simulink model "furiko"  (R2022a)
settings: Solver=VariableStepAuto  StartTime=0.0  StopTime=10.0  RelTol=1e-3
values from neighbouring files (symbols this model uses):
  k = 9e9    (= 9000000000)    [electDipole.m]    (also in solvGasSei.m = 1; solvJacobi.m = 1; solvSOR.m = 1; solvSORerr.m = 1)
  m = 4*m    (= 4)    [rom_int.m]    (also in FreeOscil_Displace_Test01.m = 1; vspring.m = 1)
undefined symbols (not defined in the file or in its folder): l

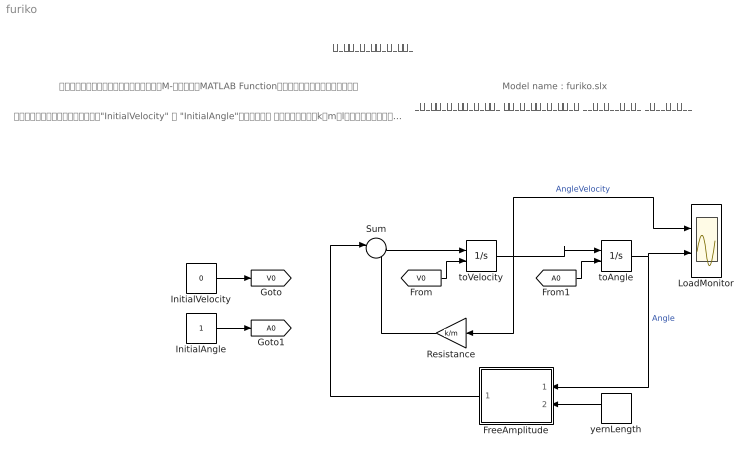
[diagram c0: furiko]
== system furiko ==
  note: コンフィギュレーションパラメータ ソルバータイプ：可変ステップ ソルバー：自動ソルバー その他：デフォルト
  note: シミュレーションの実行前に初期値"InitialVelocity" と "InitialAngle"を設定します モデルパラメータk，m，lはワークスペースで設定します k = 2e-5 空気の粘性 m = 1 オモリの質量 l = 1 糸の長さ g = 9.8 重力加速度：定数で設定
  note: このモデルは積分ブロックの初期値と関数M-ファイル（MATLAB Function）の使用方法を確認するモノです
  note: Model name : furiko.slx
  note: 振り子のシミュレーションモデル
  FreeAmplitude : MATLAB Function  TreatAsAtomicUnit=on
  InitialAngle : Constant
  InitialVelocity : Constant  Value=0
  LoadMonitor : Scope  NumInputPorts=2
  Resistance : Gain  Gain=k/m
  Sum : Sum  Inputs=|--
  toAngle : Integrator  InitialConditionSource=external
  toVelocity : Integrator  InitialConditionSource=external
  yernLength : Constant  Value=l
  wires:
  InitialVelocity/1 -> [V0]
  InitialAngle/1 -> [A0]
  Sum/1 -> toVelocity/1
  [V0] -> toVelocity/2
  toVelocity/1 -> LoadMonitor/1, Resistance/1, toAngle/1  "AngleVelocity"
  [A0] -> toAngle/2
  Resistance/1 -> Sum/2
  FreeAmplitude/1(y) -> Sum/1
  toAngle/1 -> FreeAmplitude/1(u), LoadMonitor/2  "Angle"
  yernLength/1 -> FreeAmplitude/2(len)

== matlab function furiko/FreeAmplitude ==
function y = amplitude(u, len)
%y = amplitude
%単一振り子モデルのふり角度からおもりに加わる力（重力加速度）
%を計算する
%   書式として
%   入力：角度 u
%         糸の長さ len
%   出力：力 y 正確に言えば，おもりの加速度
%特記事項
%   引数 l はグローバル変数
%       データ元はMATLAB Workspace上の変数 l とする
    g = 9.8;    % 重力加速度
    y = (g/len)*sin(u);
end
